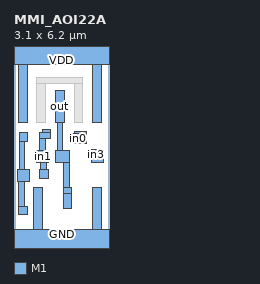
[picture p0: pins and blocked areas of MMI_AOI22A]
MACRO MMI_AOI22A
	CLASS CORE ;
	FOREIGN MMI_AOI22A 0 0 ;
	SIZE 3.1 BY 6.2 ;
	SYMMETRY X Y ;
	SITE CORE1 ;
	PIN out
		DIRECTION output ;
		USE SIGNAL ;
		PORT
			LAYER M1 ;
			RECT 1.355 3.885 1.635 4.945 ;
			LAYER M1 ;
			RECT 1.405 2.98 1.595 3.885 ;
			LAYER M1 ;
			RECT 1.36 2.6 1.795 2.98 ;
			LAYER M1 ;
			RECT 1.6 1.78 1.795 2.6 ;
			LAYER M1 ;
			RECT 1.6 1.59 1.89 1.78 ;
			LAYER M1 ;
			RECT 1.61 1.08 1.89 1.59 ;
		END
		AntennaDiffArea 1.04335 ;
	END out
	PIN in1
		DIRECTION input ;
		USE SIGNAL ;
		PORT
			LAYER M1 ;
			RECT 0.925 3.58 1.205 3.67 ;
			LAYER M1 ;
			RECT 0.82 3.39 1.205 3.58 ;
			LAYER M1 ;
			RECT 0.82 3.385 1.15 3.39 ;
			LAYER M1 ;
			RECT 0.82 2.98 1.015 3.385 ;
			LAYER M1 ;
			RECT 0.74 2.6 1.12 2.98 ;
			LAYER M1 ;
			RECT 0.875 2.35 1.07 2.6 ;
			LAYER M1 ;
			RECT 0.83 2.07 1.11 2.35 ;
		END
		AntennaGateArea 0.3465 ;
	END in1
	PIN GND
		DIRECTION inout ;
		USE GROUND ;
		PORT
			LAYER M1 ;
			RECT 0.635 0.42 0.915 1.78 ;
			LAYER M1 ;
			RECT 2.57 0.42 2.85 1.78 ;
			LAYER M1 ;
			RECT 0 -0.42 3.1 0.42 ;
		END
	END GND
	PIN in2
		DIRECTION input ;
		USE SIGNAL ;
		PORT
			LAYER M1 ;
			RECT 0.165 3.295 0.445 3.575 ;
			LAYER M1 ;
			RECT 0.165 2.36 0.355 3.295 ;
			LAYER M1 ;
			RECT 0.12 1.98 0.5 2.36 ;
			LAYER M1 ;
			RECT 0.155 1.17 0.35 1.98 ;
			LAYER M1 ;
			RECT 0.155 0.89 0.435 1.17 ;
		END
		AntennaGateArea 0.3465 ;
	END in2
	PIN VDD
		DIRECTION inout ;
		USE POWER ;
		PORT
			LAYER M1 ;
			RECT 0 5.78 3.1 6.62 ;
			LAYER M1 ;
			RECT 0.16 3.885 0.44 5.78 ;
			LAYER M1 ;
			RECT 2.56 3.885 2.84 5.78 ;
		END
	END VDD
	PIN in3
		DIRECTION input ;
		USE SIGNAL ;
		PORT
			LAYER M1 ;
			RECT 2.435 2.975 2.715 3.015 ;
			LAYER M1 ;
			RECT 2.435 2.735 2.91 2.975 ;
			LAYER M1 ;
			RECT 2.535 2.6 2.91 2.735 ;
		END
		AntennaGateArea 0.3465 ;
	END in3
	PIN in0
		DIRECTION input ;
		USE SIGNAL ;
		PORT
			LAYER M1 ;
			RECT 1.98 3.53 2.36 3.6 ;
			LAYER M1 ;
			RECT 1.795 3.25 2.36 3.53 ;
			LAYER M1 ;
			RECT 1.98 3.22 2.36 3.25 ;
		END
		AntennaGateArea 0.3465 ;
	END in0
	OBS
		LAYER M1 ;
		RECT 0.755 5.355 2.245 5.36 ;
		LAYER M1 ;
		RECT 0.75 5.165 2.25 5.355 ;
		LAYER M1 ;
		RECT 0.75 3.885 1.03 5.165 ;
		LAYER M1 ;
		RECT 1.97 3.885 2.25 5.165 ;
	END
END MMI_AOI22A
